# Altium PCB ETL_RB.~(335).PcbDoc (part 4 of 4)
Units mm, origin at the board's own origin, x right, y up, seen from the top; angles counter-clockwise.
Board outline 130.3 x 56.5 mm, 8 copper layers (Top Layer, plane 1, M1, plane 2, plane 3, M2, plane 4, Bottom Layer), stack 0.972 mm thick; 202 components, 189 nets, 1845 pads, 894 vias.
Unrouted connection lines stored in the file: 411.

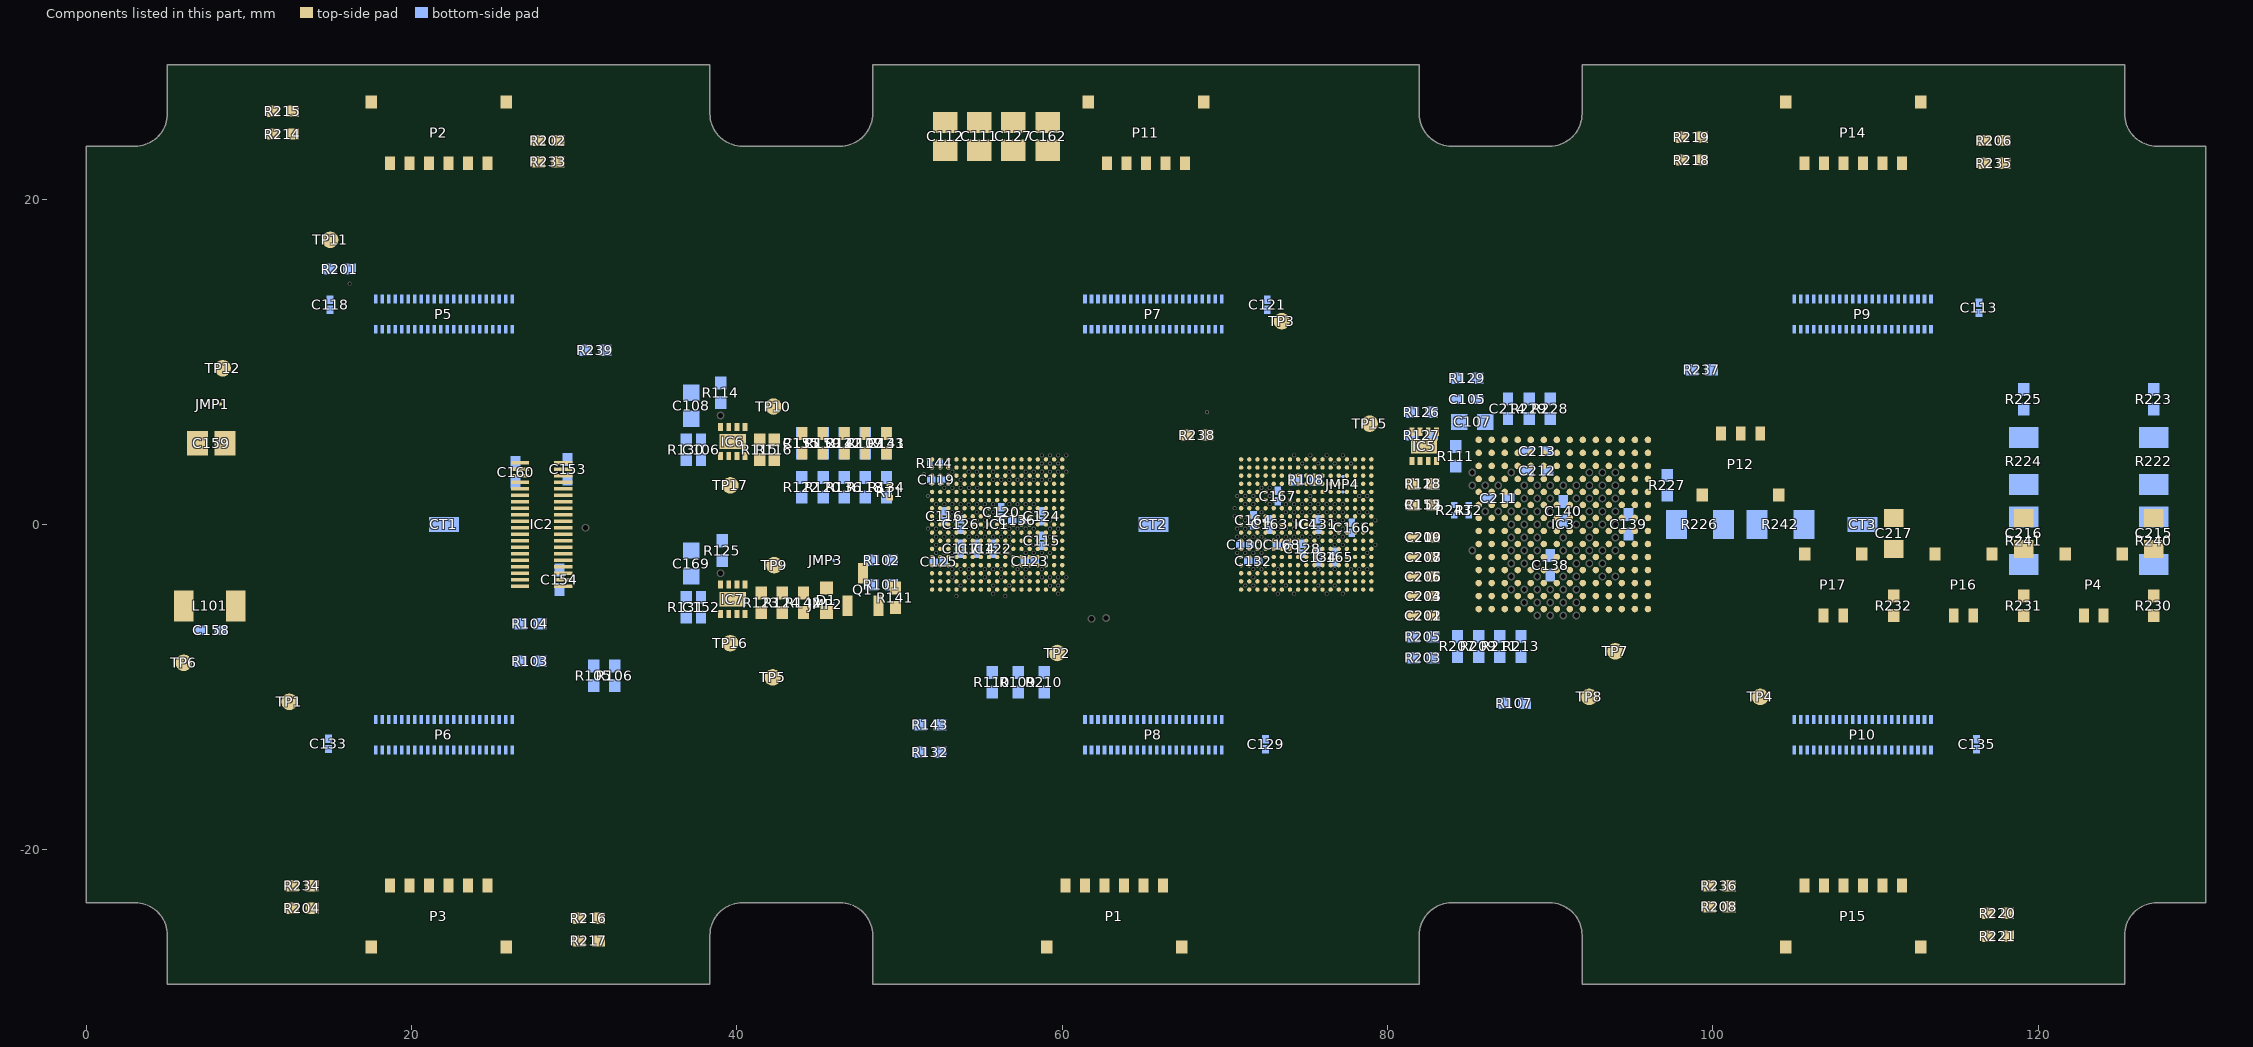
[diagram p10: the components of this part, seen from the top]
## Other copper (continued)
Bottom Layer:
  rectangle net GND: 58.7,12.425 70.1,13.425
  rectangle net GND: 26.1,2.1 27.9,3.1
  rectangle net GND: 28.2,2.4 29.9,3.3
  rectangle net GND: 28.1,-3.3 29.4,-2.4
  rectangle net GND: 37.5,-5.1 38.7,-3.9
  rectangle net GND: 37.5,4.6 38.7,5.6
  rectangle net GND: 14.8,9.3 17.9,12.7
  rectangle net GND: 58.7,9.3 61.4,12.6
  rectangle net GND: 63.7,9.3 65.5,12.6
  rectangle net GND: 107.3,9.3 109.1,12.6
  rectangle net GND: 101.7,9.3 105.1,13.425
  rectangle net GND: 101.7,12.425 113.7,13.425
  rectangle net GND: 20.1,9.3 21.9,12.6
  rectangle net GND: 22.1,-12.6 23.9,-11.4
  rectangle net GND: 22.1,-11.5 24.7,-9.3
  rectangle net GND: 110.1,-12.6 111.1,-11.4
  rectangle net GND: 110.1,-11.5 111.9,-9.3
  rectangle net GND: 113.3,-12.7 116.7,-9.3
  rectangle net GND: 67.4,-11.5 68.3,-9.3
  rectangle net GND: 66.1,-12.6 67.5,-9.3
  rectangle net GND: 69.7,-12.7 73.1,-9.3
  rectangle net GND: 26.1,-12.7 29.5,-9.3
  region net GND: 29.5,-12.425 17.5,-12.425 17.5,-13.425 29.5,-13.425
  region net GND: 73.1,-12.425 61.1,-12.425 61.1,-13.425 73.1,-13.425
  region net GND: 116.7,-12.425 104.7,-12.425 104.7,-13.425 116.7,-13.425
  rectangle net GND: 14.8,12.4 26.3,13.4
  rectangle net 1V2_RB: 5.6,-7.2 7.5,-5.8
  rectangle net LV_RB: 35.9,-5.1 37.2,-3.9
  rectangle net I_2V5RX: 36.5,-6.4 39.3,-5.3
  rectangle net I_2V5TX: 36.5,3.3 39.3,4.4
  rectangle net LV_RB: 35.7,4.6 37.3,5.8
  rectangle net 1V2T: 25.3,3.4 26.3,4.2
  rectangle net 2V5TX: 29.85,3.6 30.65,4.4
  rectangle net 2V5RX: 28.1,-4.4 28.9,-3.6
  rectangle net 1V2C: 67.7,9.275 69.5,12.275
  rectangle net 1V2C: 65.7,9.275 67.5,12.275
  rectangle net 1V2D: 109.3,9.275 111.1,12.275
  rectangle net 1V2C: 111.3,9.275 113.1,12.275
  region net 1V2D: 109.1,-9.275 107.3,-9.275 107.3,-12.275 109.1,-12.275
  region net 1V2D: 107.1,-9.275 105.3,-9.275 105.3,-12.275 107.1,-12.275
  region net 1V2B: 65.5,-9.275 63.7,-9.275 63.7,-12.275 65.5,-12.275
  region net 1V2B: 63.5,-9.275 61.7,-9.275 61.7,-12.275 63.5,-12.275
  region net 1V2B: 19.9,-9.275 18.1,-9.275 18.1,-12.275 19.9,-12.275
  region net 1V2A: 21.9,-9.275 20.1,-9.275 20.1,-12.275 21.9,-12.275
  rectangle net 1V2A: 22.1,9.275 23.9,12.275
  rectangle net 1V2A: 24.1,9.275 25.9,12.275
plane 2 (plane layer: these items are gaps in the copper):
  lines w0.152: 21.4,12.2 29.4,12.2 ; 70.8,28.3 70.8,14.1 69.2,12.5 65.6,12.5 65.6,11.4 65.6,8.7 72.9,8.7 80.2,16 113.7,16 ; 107.9,11.6 111.2,11.6 ; 109.7,-28.3 109.7,-27.5 109.7,-15.8 112,-15.8 112.5,-15.3 112.5,-11.5 109.7,-11.5 106.4,-11.5 101.7,-11.5 101.7,5.8 101.7,7 107,7 107,11.6 111.2,11.6 ; 113.67,15.97 113.67,13.47 111.8,11.6 111.2,11.6 ; 130.3,7 111.2,7 111.2,11.6 ; 4.2,-8.4 4.2,-12.5 14.7,-23 32.1,-23 35.422,-19.678 75.1,-19.678 75.1,-8.4 60.5,-8.4 60.5,-10.6 62.1,-12.2 69.1,-12.2 69.1,-15.9 17.9,-15.9 17.3,-15.3 17.3,-14.4 20,-11.7 ; 4.2,-8.4 20,-8.4 20,-11.7 ; 4.2,-8.4 4.2,18.1 9.8,23.7 20.5,23.7 20.5,15.8 18.5,15.8 18.5,13.2 19.5,12.2 29.4,12.2 ; 20,-11.7 24,-11.7 24,-4.8 11.5,-4.8 11.5,6.1 29.4,6.1 29.4,12.2 ; 80,0.5 86,0.5 86,-7 95.2,-7 95.2,-4.4 95.2,7 80,7 80,3.8 80,0.5 ; 82.5,4.1 82.5,5.3 92,5.3 92,-4.4 89.6,-4.4 89.6,-2 89.6,2.8 83.8,2.8 82.5,4.1

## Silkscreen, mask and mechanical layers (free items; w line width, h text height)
Mechanical 1:
  the board outline again, w0.15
